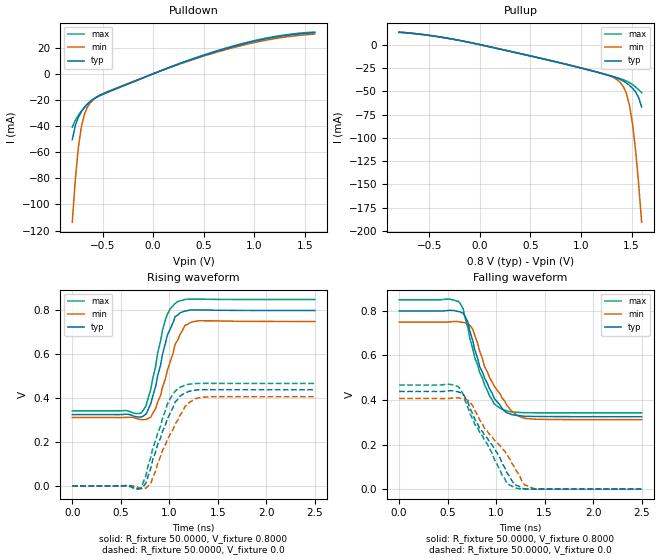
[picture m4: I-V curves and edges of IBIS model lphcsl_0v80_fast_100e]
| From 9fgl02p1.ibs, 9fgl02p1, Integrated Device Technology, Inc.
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[Model]   lphcsl_0v80_fast_100e
Model_type Output
Polarity   Non-Inverting
Enable   Active-High
Vmeas =  0.4000V
Cref =   2.0000pF
Rref =   0.0
Vref =   0.4000V
C_comp   1.1000pF   1.0000pF   1.2000pF
[Temperature Range]   25.0000   85.0000   -40.0
[Voltage Range]   0.8000V   0.7500V   0.8500V
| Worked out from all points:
|   slope of the pulldown table from 0 to 0.12 V, typ, clamps not added: 33 ohm
|   slope of the pullup table from 0 to 0.12 V, typ, clamps not added: 41.5 ohm
|   rising waveform, R_fixture 50.0000, V_fixture 0.8000: 20-80 % time 162ps typ, 186ps min, 144ps max; typ from 0.325 V to 0.8 V
|   rising waveform, R_fixture 50.0000, V_fixture 0.0: 20-80 % time 217ps typ, 248ps min, 200ps max; typ from 0 V to 0.438 V
|   falling waveform, R_fixture 50.0000, V_fixture 0.8000: 20-80 % time 236ps typ, 277ps min, 215ps max; typ from 0.8 V to 0.325 V
|   falling waveform, R_fixture 50.0000, V_fixture 0.0: 20-80 % time 354ps typ, 393ps min, 328ps max; typ from 0.438 V to 0 V
[Pulldown]
|Voltage   I(typ)   I(min)   I(max)
-800mV    -50.49mA   -113.6mA   -40.8mA
-770mV    -39.55mA   -80.95mA   -35.68mA
-740mV    -33.26mA   -56.57mA   -31.82mA
-710mV    -29.08mA   -40.53mA   -28.49mA
-680mV    -25.88mA   -31mA      -25.57mA
-650mV    -23.24mA   -25.46mA   -23.06mA
-590mV    -19.29mA   -19.6mA    -19.31mA
-470mV    -14.59mA   -14.21mA   -14.8mA
40mV      1.232mA    1.183mA    1.259mA
670mV     18.16mA    17.43mA    18.53mA
1.15V     27.29mA    26.19mA    27.81mA
1.6V      31.44mA    30.38mA    31.95mA
[Pullup]
|Voltage   I(typ)   I(min)   I(max)
-800mV    13.44mA    13.49mA    13.08mA
-350mV    7.452mA    7.282mA    7.462mA
220mV     -5.319mA   -5.18mA    -5.366mA
1.12V     -28.48mA   -28.19mA   -28.45mA
1.36V     -36.01mA   -37.85mA   -35.5mA
1.42V     -39.11mA   -45.18mA   -37.65mA
1.45V     -41.2mA    -52.6mA    -39.04mA
1.48V     -43.73mA   -65.24mA   -40.76mA
1.51V     -46.79mA   -85.21mA   -42.88mA
1.54V     -50.76mA   -113.3mA   -45.41mA
1.57V     -56.68mA   -148.9mA   -48.33mA
1.6V      -66.84mA   -190.6mA   -51.65mA
[Ramp]
| variable   typ   min   max
dV/dt_r  0.2631/0.2132n   0.2440/0.2452n   0.2804/0.1998n
dV/dt_f  0.2848/0.2340n   0.2629/0.2724n   0.3047/0.2125n
R_load = 50.0000
[Rising Waveform]
R_fixture= 50.0000
V_fixture= 0.8000
V_fixture_min= 0.7500
V_fixture_max= 0.8500
|time   V(typ)   V(min)   V(max)
0s        325.4mV    311.9mV    342.2mV
710ps     314.3mV    302.5mV    332.7mV
760ps     327.4mV    302.9mV    365.2mV
860ps     454.5mV    353mV      545.9mV
960ps     650.4mV    488.3mV    756.8mV
1.06ns    771.6mV    645.6mV    832.1mV
1.09ns    780.2mV    667.8mV    840.9mV
1.16ns    797mV      731.6mV    850mV
1.29ns    802.7mV    752.2mV    851.9mV
2.5ns     800mV      750mV      850mV
[Rising Waveform]
R_fixture= 50.0000
V_fixture= 0.0
V_fixture_min= 0.0
V_fixture_max= 0.0
|time   V(typ)   V(min)   V(max)
0s        0V         0V         0V
710ps     -12.74mV   -10.46mV   -6.455mV
760ps     14.04mV    -9.988mV   47.58mV
810ps     81.31mV    11.6mV     131.9mV
880ps     188.1mV    101.4mV    240mV
980ps     305.5mV    211.7mV    372.3mV
1.11ns    409.8mV    321.4mV    450.3mV
1.21ns    432.4mV    381.8mV    464.4mV
1.34ns    438.6mV    404.7mV    467.6mV
2.5ns     438.5mV    406.7mV    467.4mV
[Falling Waveform]
R_fixture= 50.0000
V_fixture= 0.8000
V_fixture_min= 0.7500
V_fixture_max= 0.8500
|time   V(typ)   V(min)   V(max)
0s        800mV      750mV      850mV
610ps     797.4mV    752.1mV    843.4mV
660ps     789.4mV    748.2mV    809.7mV
710ps     749.4mV    742.6mV    721.8mV
760ps     664.3mV    717.2mV    628.8mV
880ps     499.6mV    550.1mV    468.2mV
980ps     407.5mV    462.6mV    382.2mV
1.06ns    363.5mV    410.7mV    358.3mV
1.31ns    327.2mV    316.8mV    343.3mV
2.5ns     325.4mV    311.9mV    342.2mV
[Falling Waveform]
R_fixture= 50.0000
V_fixture= 0.0
V_fixture_min= 0.0
V_fixture_max= 0.0
|time   V(typ)   V(min)   V(max)
0s        438.5mV    406.7mV    467.4mV
610ps     436.7mV    409.6mV    460.2mV
660ps     426.8mV    405.6mV    426.3mV
730ps     363.1mV    390.3mV    339.3mV
880ps     242.8mV    272.8mV    219.8mV
1.06ns    117.9mV    182.8mV    64.76mV
1.21ns    16.74mV    80.12mV    3.963mV
1.29ns    1.147mV    20.48mV    571.6uV
1.41ns    203.9uV    247.7uV    93.08uV
2.5ns     0V         5.219uV    0V
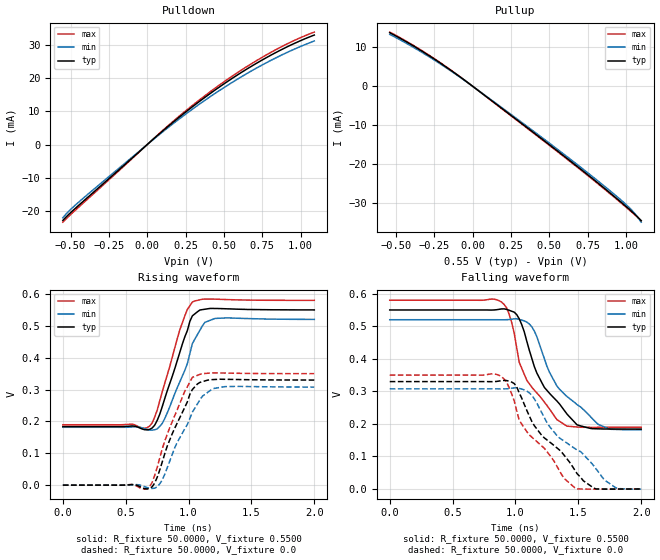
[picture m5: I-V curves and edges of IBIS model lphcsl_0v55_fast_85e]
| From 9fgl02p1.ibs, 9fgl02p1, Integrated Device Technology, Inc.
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[Model]   lphcsl_0v55_fast_85e
Model_type Output
Polarity   Inverting
Enable   Active-High
Vmeas =  0.4000V
Cref =   2.0000pF
Rref =   0.0
Vref =   0.4000V
C_comp   1.1000pF   1.0000pF   1.2000pF
[Temperature Range]   25.0000   85.0000   -40.0
[Voltage Range]   0.5500V   0.5200V   0.5800V
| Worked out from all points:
|   slope of the pulldown table from 0 to 0.083 V, typ, clamps not added: 24.5 ohm
|   slope of the pullup table from 0 to 0.083 V, typ, clamps not added: 33.4 ohm
|   rising waveform, R_fixture 50.0000, V_fixture 0.5500: 20-80 % time 183ps typ, 188ps min, 171ps max; typ from 0.184 V to 0.55 V
|   rising waveform, R_fixture 50.0000, V_fixture 0.0: 20-80 % time 207ps typ, 220ps min, 194ps max; typ from 0 V to 0.33 V
|   falling waveform, R_fixture 50.0000, V_fixture 0.5500: 20-80 % time 284ps typ, 342ps min, 253ps max; typ from 0.55 V to 0.184 V
|   falling waveform, R_fixture 50.0000, V_fixture 0.0: 20-80 % time 393ps typ, 449ps min, 348ps max; typ from 0.33 V to 0 V
[Pulldown]
|Voltage   I(typ)   I(min)   I(max)
-550mV    -22.86mA   -22.05mA   -23.4mA
-490mV    -20.12mA   -19.14mA   -20.7mA
-430mV    -17.63mA   -16.68mA   -18.17mA
50mV      2.058mA    1.922mA    2.135mA
230mV     9.045mA    8.465mA    9.373mA
410mV     15.37mA    14.42mA    15.91mA
590mV     21.04mA    19.77mA    21.74mA
770mV     26.03mA    24.5mA     26.86mA
930mV     29.87mA    28.16mA    30.76mA
1.09V     33.04mA    31.25mA    33.93mA
[Pullup]
|Voltage   I(typ)   I(min)   I(max)
-540mV    13.79mA    13.35mA    13.94mA
-360mV    9.757mA    9.424mA    9.891mA
-180mV    5.143mA    4.956mA    5.227mA
-20mV     596.4uA    573.5uA    607.4uA
340mV     -10.2mA    -9.898mA   -10.34mA
640mV     -19.35mA   -18.88mA   -19.54mA
920mV     -28.28mA   -27.72mA   -28.48mA
1.04V     -32.36mA   -32.02mA   -32.52mA
1.1V      -34.69mA   -35.06mA   -34.66mA
[Ramp]
| variable   typ   min   max
dV/dt_r  0.1979/0.2078n   0.1847/0.2401n   0.2100/0.1943n
dV/dt_f  0.2196/0.2840n   0.2029/0.3316n   0.2343/0.2729n
R_load = 50.0000
[Rising Waveform]
R_fixture= 50.0000
V_fixture= 0.5500
V_fixture_min= 0.5200
V_fixture_max= 0.5800
|time   V(typ)   V(min)   V(max)
0s        184mV      181.7mV    189.6mV
690ps     175.1mV    172.9mV    185.4mV
750ps     202.9mV    176.6mV    234.8mV
810ps     271.2mV    208.7mV    319.4mV
930ps     416.6mV    324.1mV    487.1mV
990ps     484.9mV    381.1mV    551.4mV
1.03ns    531.3mV    444mV      574.6mV
1.13ns    552.2mV    511mV      584.1mV
1.21ns    554.5mV    523.3mV    583.9mV
2ns       550mV      520.2mV    580mV
[Rising Waveform]
R_fixture= 50.0000
V_fixture= 0.0
V_fixture_min= 0.0
V_fixture_max= 0.0
|time   V(typ)   V(min)   V(max)
0s        0V         0V         0V
550ps     1.992mV    899.7uV    1.921mV
670ps     -12.01mV   -7.363mV   -11.15mV
730ps     6.349mV    -9.582mV   30.08mV
790ps     71.86mV    15.64mV    113.2mV
870ps     161.3mV    96.45mV    199.4mV
1.03ns    300.2mV    229mV      338.2mV
1.11ns    324.8mV    279.2mV    349.8mV
1.21ns    331.7mV    304.1mV    352.2mV
2ns       329.9mV    307.9mV    350mV
[Falling Waveform]
R_fixture= 50.0000
V_fixture= 0.5500
V_fixture_min= 0.5200
V_fixture_max= 0.5800
|time   V(typ)   V(min)   V(max)
0s        550mV      520mV      580mV
870ps     552mV      519.9mV    578.6mV
950ps     549mV      520.6mV    536.7mV
1.07ns    482.9mV    516.4mV    352.5mV
1.15ns    376.2mV    485.4mV    303.6mV
1.23ns    312.1mV    400.3mV    267mV
1.33ns    270.2mV    316.2mV    213.1mV
1.49ns    197.1mV    259.1mV    190.4mV
1.74ns    184.2mV    185.8mV    189.6mV
2ns       184mV      181.9mV    189.5mV
[Falling Waveform]
R_fixture= 50.0000
V_fixture= 0.0
V_fixture_min= 0.0
V_fixture_max= 0.0
|time   V(typ)   V(min)   V(max)
0s        329.9mV    307.7mV    349.9mV
870ps     331.7mV    307.6mV    349.1mV
990ps     324mV      310.6mV    270.6mV
1.07ns    260.1mV    304.5mV    187.9mV
1.15ns    194.6mV    276.9mV    152.6mV
1.33ns    126.2mV    164.2mV    69.85mV
1.47ns    59.22mV    125mV      4.447mV
1.54ns    25.17mV    106.1mV    -166.5uV
1.8ns     -314.8uV   3.333mV    -126.2uV
2ns       -24.85uV   -240.2uV   -19.95uV
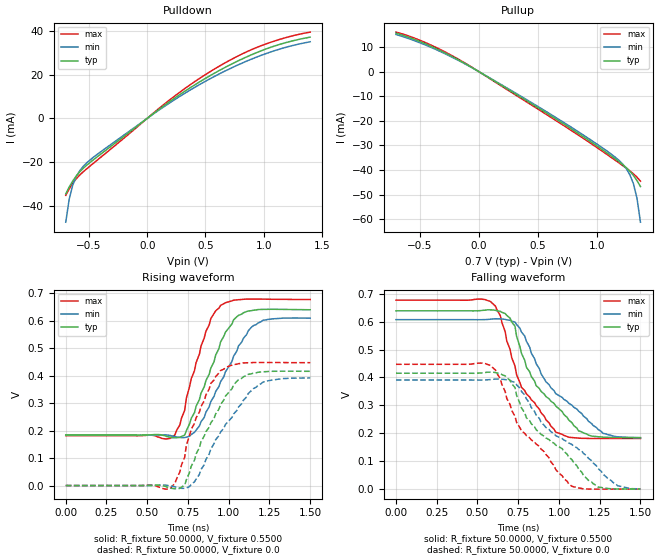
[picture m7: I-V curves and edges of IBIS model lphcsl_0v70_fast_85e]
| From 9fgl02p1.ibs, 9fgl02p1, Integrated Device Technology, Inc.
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[Model]   lphcsl_0v70_fast_85e
Model_type Output
Polarity   Inverting
Enable   Active-High
Vmeas =  0.4000V
Cref =   2.0000pF
Rref =   0.0
Vref =   0.4000V
C_comp   1.1000pF   1.0000pF   1.2000pF
[Temperature Range]   25.0000   85.0000   -40.0000
[Voltage Range]   0.7000V   0.6700V   0.7400V
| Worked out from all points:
|   slope of the pulldown table from 0 to 0.105 V, typ, clamps not added: 24.6 ohm
|   slope of the pullup table from 0 to 0.105 V, typ, clamps not added: 34.4 ohm
|   rising waveform, R_fixture 50.0000, V_fixture 0.5500: 20-80 % time 179ps typ, 220ps min, 143ps max; typ from 0.184 V to 0.64 V
|   rising waveform, R_fixture 50.0000, V_fixture 0.0: 20-80 % time 209ps typ, 243ps min, 163ps max; typ from 0 V to 0.416 V
|   falling waveform, R_fixture 50.0000, V_fixture 0.5500: 20-80 % time 282ps typ, 335ps min, 223ps max; typ from 0.639 V to 0.184 V
|   falling waveform, R_fixture 50.0000, V_fixture 0.0: 20-80 % time 368ps typ, 421ps min, 298ps max; typ from 0.415 V to 0 V
[Pulldown]
|Voltage   I(typ)   I(min)   I(max)
-700mV    -34.6mA    -47.52mA   -35.24mA
-670mV    -31.39mA   -36.87mA   -32.23mA
-640mV    -28.69mA   -30.58mA   -29.71mA
-610mV    -26.4mA    -26.67mA   -27.65mA
-550mV    -22.86mA   -21.99mA   -24.47mA
-430mV    -17.63mA   -16.5mA    -19.15mA
200mV     7.926mA    7.321mA    8.744mA
560mV     20.14mA    18.69mA    22.01mA
770mV     26.03mA    24.22mA    28.28mA
980mV     30.93mA    28.85mA    33.27mA
1.19V     34.64mA    32.5mA     36.93mA
1.4V      37.16mA    35.04mA    39.47mA
[Pullup]
|Voltage   I(typ)   I(min)   I(max)
-700mV    15.57mA    15.04mA    16.02mA
-430mV    10.81mA    10.36mA    11.32mA
-130mV    3.627mA    3.457mA    3.841mA
590mV     -17.35mA   -16.8mA    -17.95mA
890mV     -26.63mA   -25.92mA   -27.3mA
1.13V     -34.56mA   -33.83mA   -35.16mA
1.22V     -37.82mA   -37.66mA   -38.23mA
1.25V     -39.06mA   -39.49mA   -39.29mA
1.28V     -40.5mA    -41.94mA   -40.38mA
1.31V     -42.21mA   -45.54mA   -41.56mA
1.34V     -44.27mA   -51.36mA   -42.91mA
1.37V     -46.73mA   -61.22mA   -44.56mA
[Ramp]
| variable   typ   min   max
dV/dt_r  0.2495/0.2094n   0.2350/0.2416n   0.2683/0.1772n
dV/dt_f  0.2781/0.2592n   0.2585/0.3005n   0.3038/0.2197n
R_load = 50.0000
[Rising Waveform]
R_fixture= 50.0000
V_fixture= 0.5500
V_fixture_min= 0.5200
V_fixture_max= 0.5800
|time   V(typ)   V(min)   V(max)
0s        184mV      183.2mV    181.4mV
640ps     176.1mV    182.7mV    171.6mV
670ps     173.5mV    178.6mV    184.6mV
730ps     183.9mV    174.6mV    274.2mV
770ps     244.7mV    185.8mV    389.1mV
860ps     382.2mV    267mV      561.7mV
950ps     522.6mV    378.3mV    655.6mV
1.03ns    603.2mV    471mV      674.9mV
1.15ns    638mV      581.6mV    678.7mV
1.5ns     639.8mV    609.3mV    677.1mV
[Rising Waveform]
R_fixture= 50.0000
V_fixture= 0.0
V_fixture_min= 0.0
V_fixture_max= 0.0
|time   V(typ)   V(min)   V(max)
0s        0V         0V         0V
620ps     -5.285mV   832.5uV    -13.18mV
700ps     -10.57mV   -8.542mV   49.4mV
730ps     1.863mV    -10.19mV   103.7mV
770ps     70.57mV    3.856mV    205.1mV
890ps     228.1mV    133.4mV    371.8mV
950ps     295mV      195mV      418.6mV
1.06ns    385mV      285.9mV    443.5mV
1.21ns    414.1mV    376.7mV    448mV
1.5ns     415.8mV    391.6mV    447.2mV
[Falling Waveform]
R_fixture= 50.0000
V_fixture= 0.5500
V_fixture_min= 0.5200
V_fixture_max= 0.5800
|time   V(typ)   V(min)   V(max)
0s        638.8mV    607.1mV    677mV
580ps     642.2mV    608.6mV    672.2mV
640ps     637mV      609.9mV    621.5mV
730ps     583.6mV    598.4mV    441.3mV
770ps     486.2mV    562.4mV    364.4mV
860ps     370.6mV    449.2mV    299.1mV
980ps     297.8mV    341.9mV    204mV
1.12ns    208.5mV    279.4mV    182.4mV
1.27ns    185.8mV    199.6mV    181.3mV
1.5ns     184.1mV    184mV      181.3mV
[Falling Waveform]
R_fixture= 50.0000
V_fixture= 0.0
V_fixture_min= 0.0
V_fixture_max= 0.0
|time   V(typ)   V(min)   V(max)
0s        415.1mV    390.8mV    447.1mV
580ps     418.9mV    392.3mV    442.9mV
640ps     413.8mV    394mV      395.1mV
730ps     364mV      382.3mV    260.8mV
800ps     255.4mV    323.1mV    191.5mV
920ps     183.1mV    220.5mV    123.8mV
1.08ns    105mV      159.4mV    9.87mV
1.24ns    6.837mV    73.21mV    -452.8uV
1.36ns    334.7uV    11.55mV    -199.4uV
1.5ns     -41.3uV    389.7uV    -23.14uV
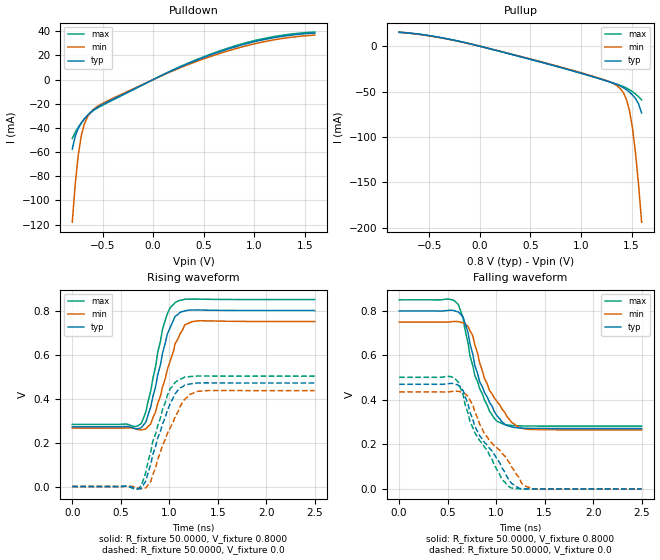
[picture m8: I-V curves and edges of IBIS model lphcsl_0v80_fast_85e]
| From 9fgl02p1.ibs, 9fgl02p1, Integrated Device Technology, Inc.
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[Model]   lphcsl_0v80_fast_85e
Model_type Output
Polarity   Inverting
Enable   Active-High
Vmeas =  0.4000V
Cref =   2.0000pF
Rref =   0.0
Vref =   0.4000V
C_comp   1.1000pF   1.0000pF   1.2000pF
[Temperature Range]   25.0000   85.0000   -40.0
[Voltage Range]   0.8000V   0.7500V   0.8500V
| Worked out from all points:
|   slope of the pulldown table from 0 to 0.12 V, typ, clamps not added: 24.7 ohm
|   slope of the pullup table from 0 to 0.12 V, typ, clamps not added: 35.2 ohm
|   rising waveform, R_fixture 50.0000, V_fixture 0.8000: 20-80 % time 165ps typ, 193ps min, 158ps max; typ from 0.272 V to 0.8 V
|   rising waveform, R_fixture 50.0000, V_fixture 0.0: 20-80 % time 206ps typ, 237ps min, 197ps max; typ from 0 V to 0.471 V
|   falling waveform, R_fixture 50.0000, V_fixture 0.8000: 20-80 % time 236ps typ, 279ps min, 213ps max; typ from 0.8 V to 0.272 V
|   falling waveform, R_fixture 50.0000, V_fixture 0.0: 20-80 % time 348ps typ, 400ps min, 322ps max; typ from 0.471 V to 0 V
[Pulldown]
|Voltage   I(typ)   I(min)   I(max)
-800mV    -57.5mA    -118mA     -48.67mA
-770mV    -46.59mA   -85.85mA   -43.39mA
-740mV    -40.19mA   -61.9mA    -39.31mA
-710mV    -35.84mA   -46.06mA   -35.76mA
-680mV    -32.42mA   -36.54mA   -32.6mA
-650mV    -29.55mA   -30.89mA   -29.85mA
-620mV    -27.13mA   -27.25mA   -27.51mA
-560mV    -23.38mA   -22.64mA   -23.91mA
130mV     5.245mA    4.902mA    5.439mA
640mV     22.49mA    21.15mA    23.23mA
1.12V     33.55mA    31.75mA    34.44mA
1.6V      38.53mA    36.86mA    39.36mA
[Pullup]
|Voltage   I(typ)   I(min)   I(max)
-800mV    15.6mA     15.6mA     15.19mA
-410mV    9.958mA    9.715mA    9.961mA
70mV      -1.984mA   -1.918mA   -2.008mA
1.03V     -30.65mA   -30.15mA   -30.73mA
1.36V     -42.39mA   -43.87mA   -42mA
1.42V     -45.75mA   -51.28mA   -44.47mA
1.45V     -47.95mA   -58.62mA   -46mA
1.48V     -50.57mA   -71.02mA   -47.85mA
1.51V     -53.7mA    -90.53mA   -50.08mA
1.54V     -57.7mA    -118mA     -52.7mA
1.57V     -63.58mA   -152.8mA   -55.69mA
1.6V      -73.58mA   -193.8mA   -59.07mA
[Ramp]
| variable   typ   min   max
dV/dt_r  0.2824/0.2046n   0.2616/0.2340n   0.3011/0.1962n
dV/dt_f  0.3170/0.2366n   0.2906/0.2741n   0.3405/0.2143n
R_load = 50.0000
[Rising Waveform]
R_fixture= 50.0000
V_fixture= 0.8000
V_fixture_min= 0.7500
V_fixture_max= 0.8500
|time   V(typ)   V(min)   V(max)
0s        271.6mV    265.6mV    282.5mV
710ps     267mV      257.4mV    285.9mV
760ps     294.8mV    262.8mV    341.5mV
810ps     363.7mV    285.4mV    436.3mV
930ps     605mV      452.3mV    714.2mV
1.01ns    723.1mV    571.4mV    813.5mV
1.09ns    782.5mV    671.7mV    843.7mV
1.16ns    798.4mV    735.3mV    851.2mV
1.26ns    802.7mV    751.5mV    852.2mV
2.5ns     800mV      750mV      850mV
[Rising Waveform]
R_fixture= 50.0000
V_fixture= 0.0
V_fixture_min= 0.0
V_fixture_max= 0.0
|time   V(typ)   V(min)   V(max)
0s        0V         0V         0V
710ps     -8.241mV   -10.16mV   2.663mV
760ps     26.72mV    -5.584mV   67.44mV
810ps     101.9mV    23.23mV    158.7mV
880ps     219.2mV    121.8mV    275.3mV
980ps     346.1mV    241.9mV    414.3mV
1.11ns    447.6mV    362.5mV    487.8mV
1.21ns    465.9mV    419.1mV    499.8mV
1.29ns    470.5mV    432.6mV    502.2mV
2.5ns     470.6mV    436mV      501.8mV
[Falling Waveform]
R_fixture= 50.0000
V_fixture= 0.8000
V_fixture_min= 0.7500
V_fixture_max= 0.8500
|time   V(typ)   V(min)   V(max)
0s        800mV      750mV      850mV
610ps     795.2mV    752.2mV    829.2mV
660ps     772mV      746.8mV    765.8mV
710ps     703.6mV    730.5mV    657.3mV
780ps     555.5mV    647.6mV    510.6mV
880ps     433.4mV    496.7mV    399.3mV
1.01ns    328.1mV    392.7mV    303.8mV
1.16ns    278.7mV    299.2mV    285.5mV
1.26ns    273.5mV    272.9mV    283.4mV
2.5ns     271.6mV    265.6mV    282.5mV
[Falling Waveform]
R_fixture= 50.0000
V_fixture= 0.0
V_fixture_min= 0.0
V_fixture_max= 0.0
|time   V(typ)   V(min)   V(max)
0s        470.6mV    436mV      501.8mV
580ps     471.2mV    439.6mV    494mV
660ps     441.9mV    433.4mV    421.5mV
780ps     282.7mV    346.7mV    253mV
880ps     208.8mV    247.7mV    187.9mV
1.06ns    94.8mV     160.3mV    42.16mV
1.14ns    35.84mV    116.1mV    7.822mV
1.26ns    986.4uV    27.4mV     -297.4uV
1.39ns    -34.06uV   -827.5uV   -7.989uV
2.5ns     0V         1.813uV    0V
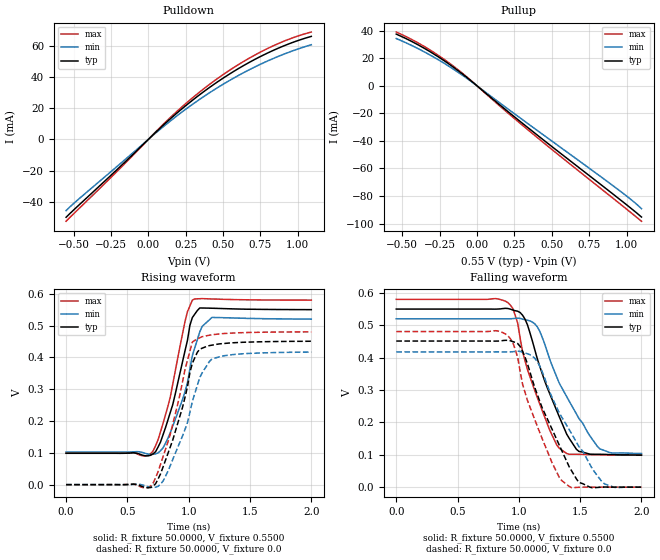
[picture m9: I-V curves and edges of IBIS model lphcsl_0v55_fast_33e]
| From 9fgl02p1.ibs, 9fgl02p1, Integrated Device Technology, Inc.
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[Model]   lphcsl_0v55_fast_33e
Model_type Output
Polarity   Inverting
Enable   Active-High
Vmeas =  0.4000V
Cref =   2.0000pF
Rref =   0.0
Vref =   0.4000V
C_comp   1.1000pF   1.0000pF   1.2000pF
[Temperature Range]   25.0000   85.0000   -40.0
[Voltage Range]   0.5500V   0.5200V   0.5800V
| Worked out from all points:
|   slope of the pulldown table from 0 to 0.083 V, typ, clamps not added: 10.9 ohm
|   slope of the pullup table from 0 to 0.083 V, typ, clamps not added: 10.9 ohm
|   rising waveform, R_fixture 50.0000, V_fixture 0.5500: 20-80 % time 174ps typ, 183ps min, 162ps max; typ from 0.099 V to 0.55 V
|   rising waveform, R_fixture 50.0000, V_fixture 0.0: 20-80 % time 192ps typ, 213ps min, 187ps max; typ from 0 V to 0.451 V
|   falling waveform, R_fixture 50.0000, V_fixture 0.5500: 20-80 % time 258ps typ, 320ps min, 232ps max; typ from 0.55 V to 0.099 V
|   falling waveform, R_fixture 50.0000, V_fixture 0.0: 20-80 % time 291ps typ, 347ps min, 251ps max; typ from 0.451 V to 0 V
[Pulldown]
|Voltage   I(typ)   I(min)   I(max)
-550mV    -50.08mA   -45.78mA   -52.65mA
-470mV    -42.74mA   -38.74mA   -45.07mA
-210mV    -19.46mA   -17.46mA   -20.63mA
130mV     11.78mA    10.51mA    12.52mA
250mV     21.68mA    19.4mA     23.02mA
390mV     32.07mA    28.79mA    33.99mA
570mV     43.66mA    39.38mA    46.13mA
750mV     53.32mA    48.34mA    56.16mA
930mV     61.07mA    55.69mA    64.05mA
1.09V     66.25mA    60.88mA    69.05mA
[Pullup]
|Voltage   I(typ)   I(min)   I(max)
-540mV    37.52mA    34.32mA    39.03mA
-440mV    32.37mA    29.43mA    33.82mA
-340mV    26.43mA    23.9mA     27.73mA
-240mV    19.68mA    17.7mA     20.72mA
-140mV    12.09mA    10.82mA    12.77mA
360mV     -32.05mA   -29mA      -33.69mA
920mV     -79.46mA   -73.36mA   -82.52mA
1.02V     -88.05mA   -81.67mA   -91.22mA
1.1V      -95.23mA   -89.17mA   -98.31mA
[Ramp]
| variable   typ   min   max
dV/dt_r  0.2705/0.2030n   0.2501/0.2328n   0.2882/0.1875n
dV/dt_f  0.2704/0.2577n   0.2495/0.3098n   0.2886/0.2471n
R_load = 50.0000
[Rising Waveform]
R_fixture= 50.0000
V_fixture= 0.5500
V_fixture_min= 0.5200
V_fixture_max= 0.5800
|time   V(typ)   V(min)   V(max)
0s        98.56mV    102.4mV    98.79mV
630ps     91.81mV    100.4mV    90.31mV
710ps     97.01mV    95.39mV    106.1mV
790ps     156mV      115mV      191.6mV
850ps     227.1mV    163.9mV    275.5mV
970ps     420.7mV    292.4mV    513mV
1.03ns    525.4mV    406mV      580.1mV
1.11ns    555.3mV    497.6mV    584.9mV
1.19ns    554.6mV    525.7mV    583.7mV
2ns       550.2mV    520.4mV    580.1mV
[Rising Waveform]
R_fixture= 50.0000
V_fixture= 0.0
V_fixture_min= 0.0
V_fixture_max= 0.0
|time   V(typ)   V(min)   V(max)
0s        0V         0V         0V
690ps     -8.832mV   -8.747mV   -4.055mV
750ps     17.55mV    -5.516mV   40.23mV
830ps     97.21mV    41.54mV    133.4mV
970ps     274.7mV    173.5mV    362.3mV
1.03ns    381.9mV    261.8mV    448.5mV
1.05ns    398.9mV    286.8mV    453.5mV
1.09ns    425.9mV    336.6mV    461.8mV
1.19ns    438.5mV    395.3mV    471.4mV
2ns       450.8mV    416.8mV    480.3mV
[Falling Waveform]
R_fixture= 50.0000
V_fixture= 0.5500
V_fixture_min= 0.5200
V_fixture_max= 0.5800
|time   V(typ)   V(min)   V(max)
0s        550mV      520mV      580mV
910ps     551.8mV    519.9mV    570.1mV
990ps     543.4mV    522mV      506.9mV
1.03ns    531.1mV    519mV      418.5mV
1.11ns    451.5mV    509.9mV    319.7mV
1.17ns    373.5mV    481.7mV    257.2mV
1.31ns    235.3mV    339.4mV    129.9mV
1.47ns    116.8mV    225.9mV    101.8mV
1.66ns    101.7mV    118.6mV    100.1mV
2ns       99.31mV    104.2mV    99.04mV
[Falling Waveform]
R_fixture= 50.0000
V_fixture= 0.0
V_fixture_min= 0.0
V_fixture_max= 0.0
|time   V(typ)   V(min)   V(max)
0s        451.3mV    417.7mV    480.6mV
890ps     453.6mV    417.6mV    473.3mV
970ps     447.1mV    419.3mV    425.3mV
1.03ns    420mV      416.8mV    318.2mV
1.09ns    356.4mV    409.1mV    248mV
1.17ns    265.6mV    374.4mV    169.4mV
1.33ns    129.5mV    228.9mV    30.02mV
1.49ns    14.82mV    125.1mV    -159.3uV
1.7ns     695.7uV    9.926mV    251.1uV
2ns       170.9uV    304.4uV    79.26uV
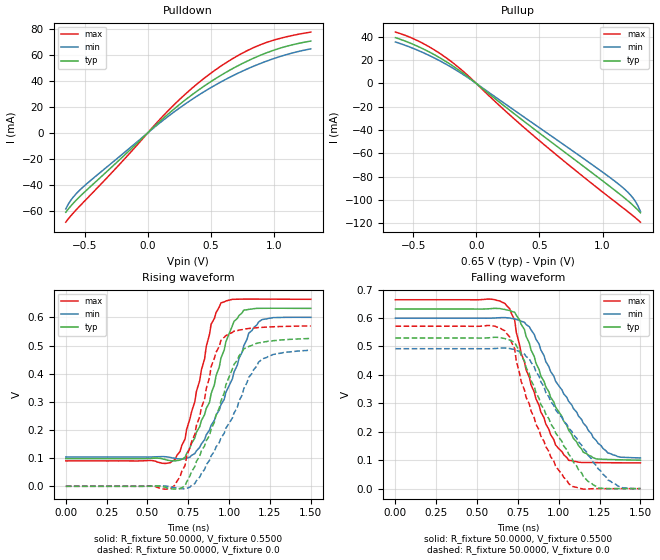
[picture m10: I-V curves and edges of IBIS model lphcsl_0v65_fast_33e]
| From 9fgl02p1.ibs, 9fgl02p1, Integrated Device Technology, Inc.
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[Model]   lphcsl_0v65_fast_33e
Model_type Output
Polarity   Inverting
Enable   Active-High
Vmeas =  0.4000V
Cref =   2.0000pF
Rref =   0.0
Vref =   0.4000V
C_comp   1.1000pF   1.0000pF   1.2000pF
[Temperature Range]   25.0000   85.0000   -40.0000
[Voltage Range]   0.6500V   0.6200V   0.6800V
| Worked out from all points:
|   slope of the pulldown table from 0 to 0.098 V, typ, clamps not added: 10.9 ohm
|   slope of the pullup table from 0 to 0.098 V, typ, clamps not added: 11.3 ohm
|   rising waveform, R_fixture 50.0000, V_fixture 0.5500: 20-80 % time 175ps typ, 209ps min, 141ps max; typ from 0.099 V to 0.632 V
|   rising waveform, R_fixture 50.0000, V_fixture 0.0: 20-80 % time 204ps typ, 237ps min, 165ps max; typ from 0 V to 0.525 V
|   falling waveform, R_fixture 50.0000, V_fixture 0.5500: 20-80 % time 251ps typ, 296ps min, 201ps max; typ from 0.632 V to 0.1 V
|   falling waveform, R_fixture 50.0000, V_fixture 0.0: 20-80 % time 279ps typ, 325ps min, 211ps max; typ from 0.53 V to 0 V
[Pulldown]
|Voltage   I(typ)   I(min)   I(max)
-650mV    -61.08mA   -58.52mA   -68.73mA
-630mV    -58.61mA   -54.84mA   -66.21mA
-590mV    -54.11mA   -49.34mA   -61.63mA
-470mV    -42.74mA   -38.03mA   -49.37mA
-210mV    -19.46mA   -17.11mA   -22.79mA
150mV     13.49mA    11.79mA    15.92mA
310mV     26.28mA    23.07mA    30.86mA
450mV     36.16mA    31.86mA    42.2mA
670mV     49.26mA    43.71mA    56.88mA
870mV     58.7mA     52.45mA    66.83mA
1.07V     65.7mA     59.29mA    73.11mA
1.29V     70.48mA    64.48mA    77.38mA
[Pullup]
|Voltage   I(typ)   I(min)   I(max)
-640mV    39.29mA    35.61mA    44.09mA
-500mV    33.59mA    30.11mA    38.48mA
-340mV    25.16mA    22.3mA     29.34mA
-180mV    14.59mA    12.79mA    17.28mA
-40mV     3.496mA    3.04mA     4.187mA
200mV     -17.47mA   -15.35mA   -20.61mA
460mV     -39.31mA   -35.02mA   -45.46mA
1.12V     -93.63mA   -85.83mA   -103.3mA
1.2V      -100.7mA   -93.35mA   -110mA
1.24V     -104.5mA   -98.2mA    -113.5mA
1.28V     -108.7mA   -105mA     -117.1mA
1.3V      -111mA     -109.9mA   -119.1mA
[Ramp]
| variable   typ   min   max
dV/dt_r  0.3151/0.1994n   0.2902/0.2356n   0.3419/0.1672n
dV/dt_f  0.3185/0.2448n   0.2942/0.2890n   0.3439/0.2022n
R_load = 50.0000
[Rising Waveform]
R_fixture= 50.0000
V_fixture= 0.5500
V_fixture_min= 0.5200
V_fixture_max= 0.5800
|time   V(typ)   V(min)   V(max)
0s        98.56mV    104.2mV    90.22mV
640ps     91.3mV     102.9mV    83.94mV
730ps     102.6mV    97.51mV    167.6mV
820ps     211.9mV    138.3mV    375.4mV
890ps     329.5mV    216.8mV    576.2mV
950ps     455.7mV    289.7mV    652mV
1.03ns    586.2mV    406.2mV    664.5mV
1.12ns    628.7mV    543.8mV    665.3mV
1.18ns    632.4mV    583.5mV    665.2mV
1.5ns     632.1mV    600.3mV    664.4mV
[Rising Waveform]
R_fixture= 50.0000
V_fixture= 0.0
V_fixture_min= 0.0
V_fixture_max= 0.0
|time   V(typ)   V(min)   V(max)
0s        0V         0V         0V
620ps     -5.769mV   226.5uV    -10.02mV
670ps     -10mV      -5.073mV   4.795mV
710ps     -5.425mV   -8.739mV   52.63mV
790ps     70.02mV    9.57mV     184.7mV
890ps     203.4mV    108.4mV    425.6mV
950ps     303mV      171.6mV    518.7mV
1.06ns    462.9mV    302.5mV    554.9mV
1.18ns    509.6mV    441.1mV    564.1mV
1.5ns     525.2mV    483.6mV    569.8mV
[Falling Waveform]
R_fixture= 50.0000
V_fixture= 0.5500
V_fixture_min= 0.5200
V_fixture_max= 0.5800
|time   V(typ)   V(min)   V(max)
0s        631.7mV    599.5mV    664.2mV
610ps     634mV      600mV      664.1mV
730ps     620.1mV    597.2mV    593mV
770ps     577.7mV    588.6mV    475.2mV
890ps     396mV      487.7mV    269.7mV
980ps     287.3mV    378.4mV    154.2mV
1.06ns    205.9mV    307.3mV    99.88mV
1.15ns    128.1mV    230.4mV    92.03mV
1.3ns     102.7mV    125.7mV    91.17mV
1.5ns     100.3mV    108.1mV    90.67mV
[Falling Waveform]
R_fixture= 50.0000
V_fixture= 0.0
V_fixture_min= 0.0
V_fixture_max= 0.0
|time   V(typ)   V(min)   V(max)
0s        529.7mV    492.1mV    571.1mV
610ps     532.3mV    492.7mV    571mV
670ps     527.8mV    494.5mV    554.9mV
730ps     514.5mV    489.4mV    491.7mV
770ps     468mV      477.9mV    376.1mV
860ps     337.8mV    411.9mV    226.7mV
1.06ns    121.6mV    213.4mV    18.03mV
1.24ns    2.086mV    70.6mV     181.5uV
1.36ns    230.9uV    9.967mV    174.9uV
1.5ns     418.1uV    214.9uV    170.6uV
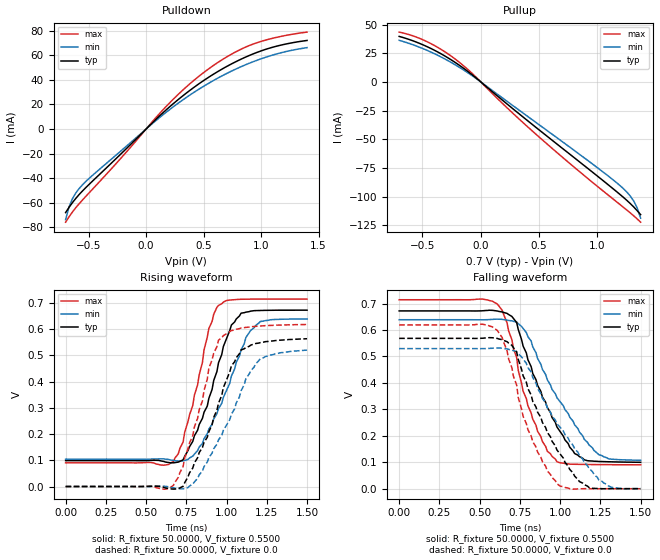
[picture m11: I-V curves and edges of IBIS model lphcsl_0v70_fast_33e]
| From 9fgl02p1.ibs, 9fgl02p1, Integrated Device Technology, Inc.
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[Model]   lphcsl_0v70_fast_33e
Model_type Output
Polarity   Inverting
Enable   Active-High
Vmeas =  0.4000V
Cref =   2.0000pF
Rref =   0.0
Vref =   0.4000V
C_comp   1.1000pF   1.0000pF   1.2000pF
[Temperature Range]   25.0000   85.0000   -40.0000
[Voltage Range]   0.7000V   0.6700V   0.7400V
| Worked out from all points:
|   slope of the pulldown table from 0 to 0.105 V, typ, clamps not added: 10.9 ohm
|   slope of the pullup table from 0 to 0.105 V, typ, clamps not added: 11.6 ohm
|   rising waveform, R_fixture 50.0000, V_fixture 0.5500: 20-80 % time 177ps typ, 214ps min, 142ps max; typ from 0.099 V to 0.672 V
|   rising waveform, R_fixture 50.0000, V_fixture 0.0: 20-80 % time 204ps typ, 239ps min, 166ps max; typ from 0 V to 0.563 V
|   falling waveform, R_fixture 50.0000, V_fixture 0.5500: 20-80 % time 239ps typ, 287ps min, 178ps max; typ from 0.672 V to 0.1 V
|   falling waveform, R_fixture 50.0000, V_fixture 0.0: 20-80 % time 263ps typ, 317ps min, 197ps max; typ from 0.568 V to 0 V
[Pulldown]
|Voltage   I(typ)   I(min)   I(max)
-700mV    -68.01mA   -73.7mA    -75.8mA
-670mV    -63.71mA   -63.29mA   -71.42mA
-640mV    -59.83mA   -56.58mA   -67.45mA
-580mV    -53.07mA   -48.2mA    -60.55mA
-520mV    -47.27mA   -42.3mA    -54.39mA
170mV     15.18mA    13.27mA    17.9mA
320mV     27.03mA    23.73mA    31.72mA
470mV     37.47mA    33.03mA    43.69mA
680mV     49.79mA    44.19mA    57.46mA
890mV     59.52mA    53.22mA    67.62mA
1.13V     67.27mA    60.95mA    74.47mA
1.4V      72.06mA    66.21mA    78.86mA
[Pullup]
|Voltage   I(typ)   I(min)   I(max)
-700mV    39.71mA    36.3mA     43.49mA
-580mV    35.81mA    32.37mA    40.12mA
-460mV    30.74mA    27.51mA    35.06mA
-220mV    17.02mA    14.97mA    19.97mA
-70mV     5.896mA    5.136mA    7.022mA
350mV     -29.63mA   -26.26mA   -34.41mA
770mV     -63.63mA   -57.46mA   -71.78mA
1.1V      -90.4mA    -82.71mA   -99.38mA
1.25V     -103.2mA   -95.91mA   -111.7mA
1.31V     -109mA     -103.8mA   -116.8mA
1.34V     -112.3mA   -109.8mA   -119.5mA
1.37V     -115.8mA   -118.9mA   -122.4mA
[Ramp]
| variable   typ   min   max
dV/dt_r  0.3379/0.2016n   0.3118/0.2342n   0.3704/0.1701n
dV/dt_f  0.3430/0.2325n   0.3182/0.2764n   0.3742/0.1901n
R_load = 50.0000
[Rising Waveform]
R_fixture= 50.0000
V_fixture= 0.5500
V_fixture_min= 0.5200
V_fixture_max= 0.5800
|time   V(typ)   V(min)   V(max)
0s        98.56mV    104.2mV    90.22mV
640ps     91.44mV    103.2mV    83.9mV
730ps     101.8mV    97.48mV    169.7mV
820ps     214.5mV    136.8mV    387mV
890ps     335.9mV    219mV      602.3mV
950ps     471.8mV    297.1mV    690.1mV
1.03ns    615.4mV    420.7mV    711.2mV
1.15ns    668.3mV    595.1mV    714.1mV
1.21ns    670.8mV    628.8mV    714.2mV
1.5ns     671.9mV    638.4mV    714.2mV
[Rising Waveform]
R_fixture= 50.0000
V_fixture= 0.0
V_fixture_min= 0.0
V_fixture_max= 0.0
|time   V(typ)   V(min)   V(max)
0s        0V         0V         0V
620ps     -5.439mV   377.1uV    -9.969mV
730ps     946uV      -8.867mV   75.95mV
820ps     109.7mV    30.91mV    259.7mV
890ps     208.8mV    110.2mV    451.1mV
950ps     317.7mV    177.8mV    557.6mV
1.03ns    460mV      275.3mV    594.1mV
1.09ns    520.4mV    364.8mV    604mV
1.21ns    548.4mV    487mV      611.7mV
1.5ns     563.1mV    519.6mV    617.4mV
[Falling Waveform]
R_fixture= 50.0000
V_fixture= 0.5500
V_fixture_min= 0.5200
V_fixture_max= 0.5800
|time   V(typ)   V(min)   V(max)
0s        672mV      638.7mV    714.2mV
580ps     674.1mV    640mV      708.6mV
640ps     668.1mV    640.1mV    674.4mV
730ps     628mV      630mV      495.7mV
770ps     539mV      605.9mV    368.8mV
830ps     435.5mV    536.1mV    262.8mV
980ps     233.7mV    344.1mV    102.3mV
1.09ns    133.1mV    241.7mV    92.58mV
1.24ns    103.1mV    129mV      91.3mV
1.5ns     100mV      107.6mV    90.51mV
[Falling Waveform]
R_fixture= 50.0000
V_fixture= 0.0
V_fixture_min= 0.0
V_fixture_max= 0.0
|time   V(typ)   V(min)   V(max)
0s        568.3mV    529.7mV    619mV
580ps     570.6mV    531mV      611.6mV
640ps     563.3mV    531.3mV    571.3mV
730ps     516.3mV    518.1mV    391.6mV
770ps     426.9mV    490.2mV    273.7mV
830ps     330mV      420.1mV    177.6mV
980ps     146.8mV    246mV      19.41mV
1.12ns    27.06mV    125.5mV    -291.1uV
1.24ns    676.8uV    33.71mV    101.4uV
1.5ns     426.2uV    543.2uV    120.7uV
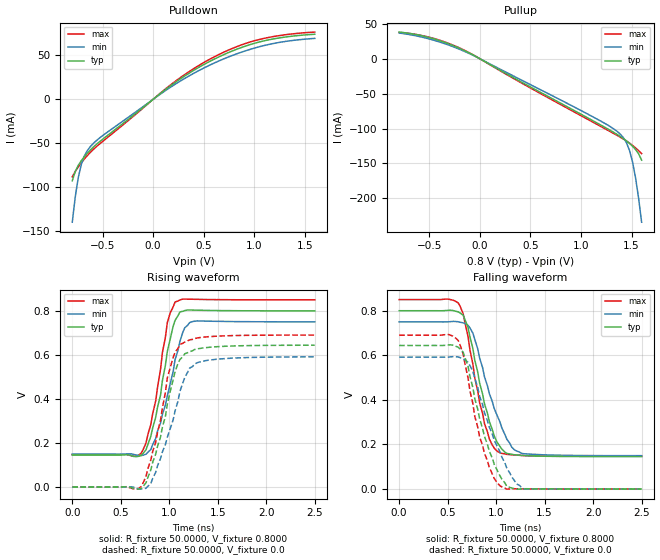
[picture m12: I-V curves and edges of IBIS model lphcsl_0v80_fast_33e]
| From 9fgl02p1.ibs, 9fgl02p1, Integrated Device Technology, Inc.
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[Model]   lphcsl_0v80_fast_33e
Model_type Output
Polarity   Inverting
Enable   Active-High
Vmeas =  0.4000V
Cref =   2.0000pF
Rref =   0.0
Vref =   0.4000V
C_comp   1.1000pF   1.0000pF   1.2000pF
[Temperature Range]   25.0000   85.0000   -40.0
[Voltage Range]   0.8000V   0.7500V   0.8500V
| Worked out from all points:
|   slope of the pulldown table from 0 to 0.12 V, typ, clamps not added: 11 ohm
|   slope of the pullup table from 0 to 0.12 V, typ, clamps not added: 12.1 ohm
|   rising waveform, R_fixture 50.0000, V_fixture 0.8000: 20-80 % time 174ps typ, 202ps min, 158ps max; typ from 0.145 V to 0.8 V
|   rising waveform, R_fixture 50.0000, V_fixture 0.0: 20-80 % time 213ps typ, 241ps min, 199ps max; typ from 0 V to 0.644 V
|   falling waveform, R_fixture 50.0000, V_fixture 0.8000: 20-80 % time 214ps typ, 254ps min, 187ps max; typ from 0.8 V to 0.145 V
|   falling waveform, R_fixture 50.0000, V_fixture 0.0: 20-80 % time 242ps typ, 292ps min, 216ps max; typ from 0.644 V to 0 V
[Pulldown]
|Voltage   I(typ)   I(min)   I(max)
-800mV    -92.57mA   -139.6mA   -88.06mA
-770mV    -81.83mA   -110.4mA   -81.92mA
-740mV    -74.86mA   -88.54mA   -76.8mA
-710mV    -69.59mA   -73.71mA   -72.12mA
-680mV    -65.11mA   -64.26mA   -67.77mA
-650mV    -61.1mA    -58.06mA   -63.76mA
-500mV    -45.44mA   -41.28mA   -47.88mA
190mV     16.84mA    15.05mA    17.9mA
610mV     45.97mA    41.51mA    48.54mA
850mV     57.86mA    52.62mA    60.82mA
1.06V     65.41mA    60.01mA    68.26mA
1.6V      73.95mA    69.24mA    76.41mA
[Pullup]
|Voltage   I(typ)   I(min)   I(max)
-800mV    38.28mA    36.96mA    37.81mA
-470mV    29.15mA    27.13mA    29.71mA
-170mV    12.86mA    11.67mA    13.38mA
970mV     -77.08mA   -71.89mA   -79.17mA
1.36V     -108.6mA   -104.3mA   -110mA
1.42V     -114.4mA   -113.2mA   -115.1mA
1.45V     -117.7mA   -120.3mA   -117.9mA
1.48V     -121.3mA   -131.3mA   -120.9mA
1.51V     -125.3mA   -147.8mA   -124.2mA
1.54V     -130mA     -170.7mA   -127.8mA
1.57V     -136.1mA   -199.7mA   -131.7mA
1.6V      -145.3mA   -234.2mA   -135.9mA
[Ramp]
| variable   typ   min   max
dV/dt_r  0.3864/0.2085n   0.3548/0.2339n   0.4141/0.1959n
dV/dt_f  0.3928/0.2120n   0.3602/0.2533n   0.4219/0.1894n
R_load = 50.0000
[Rising Waveform]
R_fixture= 50.0000
V_fixture= 0.8000
V_fixture_min= 0.7500
V_fixture_max= 0.8500
|time   V(typ)   V(min)   V(max)
0s        145.3mV    149.5mV    146.9mV
710ps     143.1mV    143mV      153.3mV
760ps     169mV      149mV      199.6mV
860ps     316.4mV    220.5mV    390.7mV
910ps     417.3mV    290.2mV    534.5mV
980ps     614.9mV    414.2mV    747.1mV
1.06ns    757mV      579mV      840.2mV
1.16ns    801.3mV    723.1mV    853.3mV
1.24ns    803.5mV    751.3mV    852.7mV
2.5ns     800mV      750.1mV    850mV
[Rising Waveform]
R_fixture= 50.0000
V_fixture= 0.0
V_fixture_min= 0.0
V_fixture_max= 0.0
|time   V(typ)   V(min)   V(max)
0s        0V         0V         0V
710ps     -6.915mV   -8.955mV   1.904mV
760ps     19.21mV    -5.318mV   47.98mV
860ps     149.8mV    66.49mV    202.7mV
980ps     376mV      226.1mV    495.9mV
1.06ns    524mV      345.9mV    612.1mV
1.11ns    579.1mV    434.7mV    647.1mV
1.21ns    614.6mV    540.1mV    668.2mV
1.31ns    629mV      567.4mV    678.4mV
2.5ns     644mV      591.3mV    690.1mV
[Falling Waveform]
R_fixture= 50.0000
V_fixture= 0.8000
V_fixture_min= 0.7500
V_fixture_max= 0.8500
|time   V(typ)   V(min)   V(max)
0s        800mV      750mV      850mV
610ps     794.8mV    750.4mV    834.7mV
660ps     780mV      745.6mV    786.7mV
760ps     630.7mV    699.5mV    560.6mV
880ps     382.1mV    503.1mV    293mV
930ps     302.7mV    427.7mV    224.5mV
1.01ns    209.8mV    330mV      169.6mV
1.16ns    155.6mV    188.4mV    153.5mV
1.26ns    150.9mV    160.2mV    150.5mV
2.5ns     145.3mV    149.6mV    146.9mV
[Falling Waveform]
R_fixture= 50.0000
V_fixture= 0.0
V_fixture_min= 0.0
V_fixture_max= 0.0
|time   V(typ)   V(min)   V(max)
0s        644.1mV    591.7mV    690.2mV
610ps     636mV      592.4mV    665.7mV
660ps     614mV      584.9mV    606mV
710ps     551.5mV    568.9mV    499.1mV
830ps     314.6mV    415.7mV    232.8mV
930ps     169.7mV    277mV      96.54mV
1.04ns    58.59mV    166.4mV    14.47mV
1.16ns    4.589mV    54.79mV    421.1uV
1.29ns    883.4uV    378uV      512.3uV
2.5ns     4.369uV    18.14uV    1.506uV
